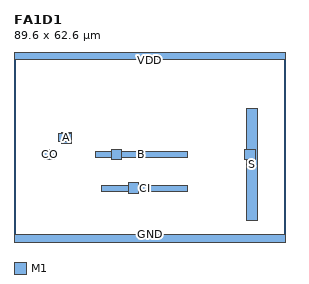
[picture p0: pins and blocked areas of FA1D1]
MACRO FA1D1
  CLASS CORE ;
  ORIGIN 0 0 ;
  SIZE 89.600 BY 62.600 ;
  SYMMETRY X Y ;
  SITE TR1um_site ;
  PIN B
    DIRECTION INPUT ; USE SIGNAL ;
    PORT
      LAYER M1 ;
        RECT 26.700 27.900 57.300 29.700 ;
      LAYER M1 ;
        RECT 32.100 27.100 35.500 30.500 ;
      LAYER M1 ;
        RECT 32.100 27.100 35.500 30.500 ;
    END
  END B
  PIN CO
    DIRECTION OUTPUT ; USE SIGNAL ;
    PORT
      LAYER M1 ;
        RECT 10.100 27.100 13.500 30.500 ;
      LAYER M1 ;
        RECT 10.100 27.100 13.500 30.500 ;
    END
  END CO
  PIN A
    DIRECTION INPUT ; USE SIGNAL ;
    PORT
      LAYER M1 ;
        RECT 15.600 32.600 19.000 36.000 ;
      LAYER M1 ;
        RECT 15.600 32.600 19.000 36.000 ;
      LAYER M1 ;
        RECT 14.700 33.000 19.100 35.600 ;
    END
  END A
  PIN CI
    DIRECTION INPUT ; USE SIGNAL ;
    PORT
      LAYER M1 ;
        RECT 28.900 16.800 57.300 18.600 ;
      LAYER M1 ;
        RECT 37.600 16.100 41.000 19.500 ;
      LAYER M1 ;
        RECT 37.600 16.100 41.000 19.500 ;
    END
  END CI
  PIN S
    DIRECTION OUTPUT ; USE SIGNAL ;
    PORT
      LAYER M1 ;
        RECT 76.500 7.200 80.300 44.000 ;
      LAYER M1 ;
        RECT 76.100 27.100 79.500 30.500 ;
      LAYER M1 ;
        RECT 76.100 27.100 79.500 30.500 ;
    END
  END S
  PIN GND
    DIRECTION INOUT ; USE GROUND ;
    PORT
      LAYER M1 ;
        RECT 0.000 0.000 89.600 2.600 ;
    END
  END GND
  PIN VDD
    DIRECTION INOUT ; USE POWER ;
    PORT
      LAYER M1 ;
        RECT 0.000 60.000 89.600 62.600 ;
    END
  END VDD
END FA1D1
